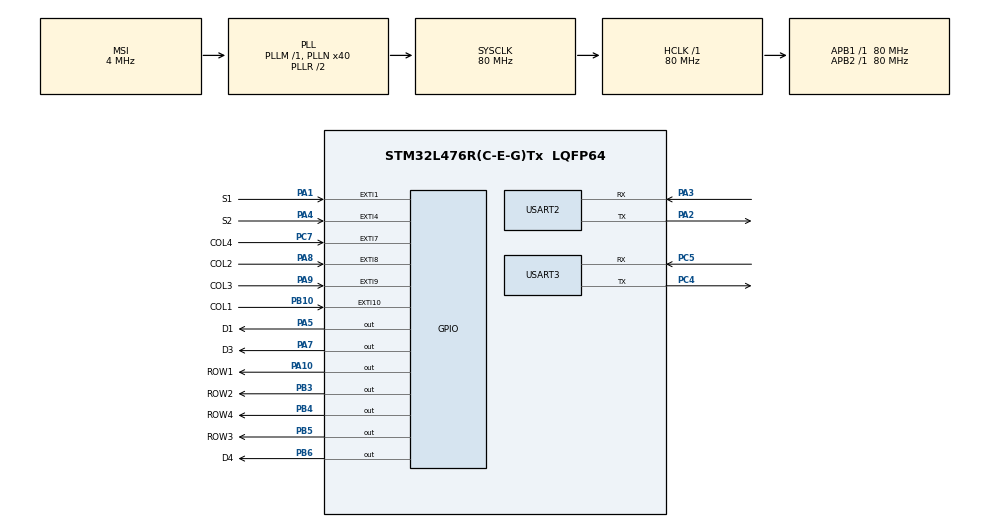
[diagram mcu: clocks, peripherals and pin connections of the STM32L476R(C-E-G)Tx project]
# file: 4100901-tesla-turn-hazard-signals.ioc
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Mcu.Family=STM32L4
Mcu.Name=STM32L476R(C-E-G)Tx
Mcu.Package=LQFP64
NVIC.EXTI15_10_IRQn=true\:0\:0\:false\:false\:true\:true\:true\:true
NVIC.EXTI1_IRQn=true\:0\:0\:false\:false\:true\:true\:true\:true
NVIC.EXTI4_IRQn=true\:0\:0\:false\:false\:true\:true\:true\:true
NVIC.EXTI9_5_IRQn=true\:0\:0\:false\:false\:true\:true\:true\:true
NVIC.PriorityGroup=NVIC_PRIORITYGROUP_4
NVIC.USART2_IRQn=true\:0\:0\:false\:false\:true\:true\:true\:true
NVIC.USART3_IRQn=true\:0\:0\:false\:false\:true\:true\:true\:true
PA1.GPIO_Label=S1
PA1.GPIO_ModeDefaultEXTI=GPIO_MODE_IT_FALLING
PA1.GPIO_PuPd=GPIO_PULLUP
PA1.Signal=GPXTI1
PA10.GPIO_Label=ROW1
PA10.PinState=GPIO_PIN_SET
PA10.Signal=GPIO_Output
PA2.Mode=Asynchronous
PA2.Signal=USART2_TX
PA3.Mode=Asynchronous
PA3.Signal=USART2_RX
PA4.GPIO_Label=S2
PA4.GPIO_ModeDefaultEXTI=GPIO_MODE_IT_FALLING
PA4.GPIO_PuPd=GPIO_PULLUP
PA4.Signal=GPXTI4
PA5.GPIO_Label=D1
PA5.PinState=GPIO_PIN_SET
PA5.Signal=GPIO_Output
PA7.GPIO_Label=D3
PA7.PinState=GPIO_PIN_SET
PA7.Signal=GPIO_Output
PA8.GPIO_Label=COL2
PA8.GPIO_PuPd=GPIO_PULLDOWN
PA8.Signal=GPXTI8
PA9.GPIO_Label=COL3
PA9.GPIO_PuPd=GPIO_PULLDOWN
PA9.Signal=GPXTI9
PB10.GPIO_Label=COL1
PB10.GPIO_PuPd=GPIO_PULLDOWN
PB10.Signal=GPXTI10
PB3\ (JTDO-TRACESWO).GPIO_Label=ROW2
PB3\ (JTDO-TRACESWO).PinState=GPIO_PIN_SET
PB3\ (JTDO-TRACESWO).Signal=GPIO_Output
PB4\ (NJTRST).GPIO_Label=ROW4
PB4\ (NJTRST).PinState=GPIO_PIN_SET
PB4\ (NJTRST).Signal=GPIO_Output
PB5.GPIO_Label=ROW3
PB5.PinState=GPIO_PIN_SET
PB5.Signal=GPIO_Output
PB6.GPIO_Label=D4
PB6.PinState=GPIO_PIN_SET
PB6.Signal=GPIO_Output
PC4.Mode=Asynchronous
PC4.Signal=USART3_TX
PC5.Mode=Asynchronous
PC5.Signal=USART3_RX
PC7.GPIO_Label=COL4
PC7.GPIO_PuPd=GPIO_PULLDOWN
PC7.Signal=GPXTI7
ProjectManager.HeapSize=0x200
ProjectManager.StackSize=0x400
ProjectManager.TargetToolchain=STM32CubeIDE
RCC.AHBFreq_Value=80000000
RCC.APB1Freq_Value=80000000
RCC.APB1TimFreq_Value=80000000
RCC.APB2Freq_Value=80000000
RCC.APB2TimFreq_Value=80000000
RCC.CortexFreq_Value=80000000
RCC.HCLKFreq_Value=80000000
RCC.HSE_VALUE=8000000
RCC.HSI_VALUE=16000000
RCC.LSE_VALUE=32768
RCC.MSI_VALUE=4000000
RCC.PLLN=40
RCC.SYSCLKFreq_VALUE=80000000
RCC.SYSCLKSource=RCC_SYSCLKSOURCE_PLLCLK
RCC.VCOOutputFreq_Value=160000000
USART2.VirtualMode-Asynchronous=VM_ASYNC
USART3.VirtualMode-Asynchronous=VM_ASYNC
board=custom

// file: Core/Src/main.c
/* USER CODE BEGIN Header */
/**
  ******************************************************************************
  * @file           : main.c
  * @brief          : Main program body
  ******************************************************************************
  * @attention
  *
  * Copyright (c) 2024 STMicroelectronics.
  * All rights reserved.
  *
  * This software is licensed under terms that can be found in the LICENSE file
  * in the root directory of this software component.
  * If no LICENSE file comes with this software, it is provided AS-IS.
  *
  ******************************************************************************
  */
/* USER CODE END Header */
#include "main.h"

/* USER CODE BEGIN Includes */
#include "ring_buffer.h"
#include "keypad.h"
/* USER CODE END Includes */

UART_HandleTypeDef huart2;
UART_HandleTypeDef huart3;

/* USER CODE BEGIN PV */
uint32_t left_toggles = 0;
uint32_t left_last_press_tick = 0;

uint8_t data_usart3;
uint8_t data_usart2;

/* control variables for ring buffer in USART3 */
#define CAPACITY_USART3 5
uint8_t mem_usart3[CAPACITY_USART3];
ring_buffer_t rb_usart3;

/* control variables for ring buffer in USART2 */
#define CAPACITY_USART2 10
uint8_t mem_usart2[CAPACITY_USART2];
ring_buffer_t rb_usart2;
/* USER CODE END PV */

void SystemClock_Config(void);
static void MX_GPIO_Init(void);
static void MX_USART2_UART_Init(void);
static void MX_USART3_UART_Init(void);
/* USER CODE BEGIN PFP */
void heartbeat(void);
/* USER CODE END PFP */

/* USER CODE BEGIN 0 */
void HAL_UART_RxCpltCallback(UART_HandleTypeDef *huart)
{
  /* Data received in USART3 */
  if (huart->Instance == USART3) {
	  ring_buffer_write(&rb_usart3, data_usart3);
	  HAL_UART_Receive_IT(&huart3, &data_usart3, 1);
  }
  /* Data received in USART2 */
  if (huart->Instance == USART2) {
	  ring_buffer_write(&rb_usart2, data_usart2); // put the data received in buffer
	  HAL_UART_Receive_IT(&huart2, &data_usart2, 1); // enable interrupt to continue receiving
  }
}

void HAL_GPIO_EXTI_Callback(uint16_t GPIO_Pin)
{
	static uint16_t last_pressed = 0xFFFF;
	static uint32_t last_tick = 0;

	if (last_pressed == GPIO_Pin) {
		if (HAL_GetTick() < (last_tick + 200)) {
			return 0;
		}
	}
	last_pressed = GPIO_Pin;
	last_tick = HAL_GetTick();

	uint8_t key_pressed = keypad_scan(GPIO_Pin);
    HAL_UART_Transmit(&huart2, &key_pressed, 1, 10);

	if (GPIO_Pin == S1_Pin) {
		HAL_UART_Transmit(&huart2, (uint8_t *)"S1\r\n", 4, 10);
		if (HAL_GetTick() < (left_last_press_tick + 300)) { // if last press was in the last 300ms
			left_toggles = 0xFFFFFF; // a long time toggling (infinite)
		} else {
			left_toggles = 6;
		}
		left_last_press_tick = HAL_GetTick();
	} else if (GPIO_Pin == S2_Pin) {
		left_toggles = 0;
	}
}

void heartbeat(void)
{
	static uint32_t heartbeat_tick = 0;
	if (heartbeat_tick < HAL_GetTick()) {
		heartbeat_tick = HAL_GetTick() + 500;
		HAL_GPIO_TogglePin(D1_GPIO_Port, D1_Pin);
	}
}

void turn_signal_left(void)
{
	static uint32_t turn_toggle_tick = 0;
	if (turn_toggle_tick < HAL_GetTick()) {
		if (left_toggles > 0) {
			turn_toggle_tick = HAL_GetTick() + 500;
			HAL_GPIO_TogglePin(D3_GPIO_Port, D3_Pin);
			left_toggles--;
		} else {
			HAL_GPIO_WritePin(D3_GPIO_Port, D3_Pin, 1);
		}

	}
}
/* USER CODE END 0 */

int main(void)
{

  /* MCU Configuration--------------------------------------------------------*/

  /* Reset of all peripherals, Initializes the Flash interface and the Systick. */
  HAL_Init();

  /* Configure the system clock */
  SystemClock_Config();

  /* Initialize all configured peripherals */
  MX_GPIO_Init();
  MX_USART2_UART_Init();
  MX_USART3_UART_Init();
  /* USER CODE BEGIN 2 */
  /* Initialize ring buffer (control, memory, and capacity) */
  ring_buffer_init(&rb_usart3, mem_usart3, CAPACITY_USART3);
  ring_buffer_init(&rb_usart2, mem_usart2, CAPACITY_USART2);
  /* USER CODE END 2 */

  /* Infinite loop */
  /* USER CODE BEGIN WHILE */
  /* Enable USART Rx interrupt to start receiving */
  HAL_UART_Receive_IT(&huart3, &data_usart3, 1);
  HAL_UART_Receive_IT(&huart2, &data_usart2, 1);
  while (1)
  {
	  uint8_t byte = 0;
	  if (ring_buffer_is_full(&rb_usart2) != 0) {
		  int8_t id_incorrect = 0;
		  char my_id[] = "1053821948";
		  for (uint8_t idx = 0; idx < sizeof(my_id); idx++) {
			  if (ring_buffer_read(&rb_usart2, &byte) != 0) { // 0x20
				  if (byte != my_id[idx]) {
					  id_incorrect = 1;
				  }
			  }
		  }
		  if (id_incorrect == 0) {
			  HAL_UART_Transmit(&huart2, "Sam C\r\n", 7, 10);
		  } else {
			  HAL_UART_Transmit(&huart2, "Error\r\n", 7, 10);
		  }
	  }
	  if (ring_buffer_is_empty(&rb_usart3) == 0) {
		  uint8_t data;
		  ring_buffer_read(&rb_usart3, &data);
		  HAL_UART_Transmit(&huart2, &data, 1, 10);
	  }
	  heartbeat();
	  turn_signal_left();
    /* USER CODE END WHILE */

  }
}

void SystemClock_Config(void)
{
  RCC_OscInitTypeDef RCC_OscInitStruct = {0};
  RCC_ClkInitTypeDef RCC_ClkInitStruct = {0};

  /** Configure the main internal regulator output voltage
  */
  if (HAL_PWREx_ControlVoltageScaling(PWR_REGULATOR_VOLTAGE_SCALE1) != HAL_OK)
  {
    Error_Handler();
  }

  /** Initializes the RCC Oscillators according to the specified parameters
  * in the RCC_OscInitTypeDef structure.
  */
  RCC_OscInitStruct.OscillatorType = RCC_OSCILLATORTYPE_MSI;
  RCC_OscInitStruct.MSIState = RCC_MSI_ON;
  RCC_OscInitStruct.MSICalibrationValue = 0;
  RCC_OscInitStruct.MSIClockRange = RCC_MSIRANGE_6;
  RCC_OscInitStruct.PLL.PLLState = RCC_PLL_ON;
  RCC_OscInitStruct.PLL.PLLSource = RCC_PLLSOURCE_MSI;
  RCC_OscInitStruct.PLL.PLLM = 1;
  RCC_OscInitStruct.PLL.PLLN = 40;
  RCC_OscInitStruct.PLL.PLLP = RCC_PLLP_DIV7;
  RCC_OscInitStruct.PLL.PLLQ = RCC_PLLQ_DIV2;
  RCC_OscInitStruct.PLL.PLLR = RCC_PLLR_DIV2;
  if (HAL_RCC_OscConfig(&RCC_OscInitStruct) != HAL_OK)
  {
    Error_Handler();
  }

  /** Initializes the CPU, AHB and APB buses clocks
  */
  RCC_ClkInitStruct.ClockType = RCC_CLOCKTYPE_HCLK|RCC_CLOCKTYPE_SYSCLK
                              |RCC_CLOCKTYPE_PCLK1|RCC_CLOCKTYPE_PCLK2;
  RCC_ClkInitStruct.SYSCLKSource = RCC_SYSCLKSOURCE_PLLCLK;
  RCC_ClkInitStruct.AHBCLKDivider = RCC_SYSCLK_DIV1;
  RCC_ClkInitStruct.APB1CLKDivider = RCC_HCLK_DIV1;
  RCC_ClkInitStruct.APB2CLKDivider = RCC_HCLK_DIV1;

  if (HAL_RCC_ClockConfig(&RCC_ClkInitStruct, FLASH_LATENCY_4) != HAL_OK)
  {
    Error_Handler();
  }
}

static void MX_USART2_UART_Init(void)
{

  huart2.Instance = USART2;
  huart2.Init.BaudRate = 115200;
  huart2.Init.WordLength = UART_WORDLENGTH_8B;
  huart2.Init.StopBits = UART_STOPBITS_1;
  huart2.Init.Parity = UART_PARITY_NONE;
  huart2.Init.Mode = UART_MODE_TX_RX;
  huart2.Init.HwFlowCtl = UART_HWCONTROL_NONE;
  huart2.Init.OverSampling = UART_OVERSAMPLING_16;
  huart2.Init.OneBitSampling = UART_ONE_BIT_SAMPLE_DISABLE;
  huart2.AdvancedInit.AdvFeatureInit = UART_ADVFEATURE_NO_INIT;
  if (HAL_UART_Init(&huart2) != HAL_OK)
  {
    Error_Handler();
  }

}

static void MX_USART3_UART_Init(void)
{

  huart3.Instance = USART3;
  huart3.Init.BaudRate = 115200;
  huart3.Init.WordLength = UART_WORDLENGTH_8B;
  huart3.Init.StopBits = UART_STOPBITS_1;
  huart3.Init.Parity = UART_PARITY_NONE;
  huart3.Init.Mode = UART_MODE_TX_RX;
  huart3.Init.HwFlowCtl = UART_HWCONTROL_NONE;
  huart3.Init.OverSampling = UART_OVERSAMPLING_16;
  huart3.Init.OneBitSampling = UART_ONE_BIT_SAMPLE_DISABLE;
  huart3.AdvancedInit.AdvFeatureInit = UART_ADVFEATURE_NO_INIT;
  if (HAL_UART_Init(&huart3) != HAL_OK)
  {
    Error_Handler();
  }

}

static void MX_GPIO_Init(void)
{
  GPIO_InitTypeDef GPIO_InitStruct = {0};

  /* GPIO Ports Clock Enable */
  __HAL_RCC_GPIOA_CLK_ENABLE();
  __HAL_RCC_GPIOC_CLK_ENABLE();
  __HAL_RCC_GPIOB_CLK_ENABLE();

  /*Configure GPIO pin Output Level */
  HAL_GPIO_WritePin(GPIOA, D1_Pin|D3_Pin|ROW1_Pin, GPIO_PIN_SET);

  /*Configure GPIO pin Output Level */
  HAL_GPIO_WritePin(GPIOB, ROW2_Pin|ROW4_Pin|ROW3_Pin|D4_Pin, GPIO_PIN_SET);

  /*Configure GPIO pins : S1_Pin S2_Pin */
  GPIO_InitStruct.Pin = S1_Pin|S2_Pin;
  GPIO_InitStruct.Mode = GPIO_MODE_IT_FALLING;
  GPIO_InitStruct.Pull = GPIO_PULLUP;
  HAL_GPIO_Init(GPIOA, &GPIO_InitStruct);

  /*Configure GPIO pins : D1_Pin D3_Pin ROW1_Pin */
  GPIO_InitStruct.Pin = D1_Pin|D3_Pin|ROW1_Pin;
  GPIO_InitStruct.Mode = GPIO_MODE_OUTPUT_PP;
  GPIO_InitStruct.Pull = GPIO_NOPULL;
  GPIO_InitStruct.Speed = GPIO_SPEED_FREQ_LOW;
  HAL_GPIO_Init(GPIOA, &GPIO_InitStruct);

  /*Configure GPIO pin : COLUMN1_Pin */
  GPIO_InitStruct.Pin = COLUMN1_Pin;
  GPIO_InitStruct.Mode = GPIO_MODE_IT_RISING;
  GPIO_InitStruct.Pull = GPIO_PULLDOWN;
  HAL_GPIO_Init(COLUMN1_GPIO_Port, &GPIO_InitStruct);

  /*Configure GPIO pin : COLUMN4_Pin */
  GPIO_InitStruct.Pin = COLUMN4_Pin;
  GPIO_InitStruct.Mode = GPIO_MODE_IT_RISING;
  GPIO_InitStruct.Pull = GPIO_PULLDOWN;
  HAL_GPIO_Init(COLUMN4_GPIO_Port, &GPIO_InitStruct);

  /*Configure GPIO pins : COLUMN2_Pin COLUMN3_Pin */
  GPIO_InitStruct.Pin = COLUMN2_Pin|COLUMN3_Pin;
  GPIO_InitStruct.Mode = GPIO_MODE_IT_RISING;
  GPIO_InitStruct.Pull = GPIO_PULLDOWN;
  HAL_GPIO_Init(GPIOA, &GPIO_InitStruct);

  /*Configure GPIO pins : ROW2_Pin ROW4_Pin ROW3_Pin D4_Pin */
  GPIO_InitStruct.Pin = ROW2_Pin|ROW4_Pin|ROW3_Pin|D4_Pin;
  GPIO_InitStruct.Mode = GPIO_MODE_OUTPUT_PP;
  GPIO_InitStruct.Pull = GPIO_NOPULL;
  GPIO_InitStruct.Speed = GPIO_SPEED_FREQ_LOW;
  HAL_GPIO_Init(GPIOB, &GPIO_InitStruct);

  /* EXTI interrupt init*/
  HAL_NVIC_SetPriority(EXTI1_IRQn, 0, 0);
  HAL_NVIC_EnableIRQ(EXTI1_IRQn);

  HAL_NVIC_SetPriority(EXTI4_IRQn, 0, 0);
  HAL_NVIC_EnableIRQ(EXTI4_IRQn);

  HAL_NVIC_SetPriority(EXTI9_5_IRQn, 0, 0);
  HAL_NVIC_EnableIRQ(EXTI9_5_IRQn);

  HAL_NVIC_SetPriority(EXTI15_10_IRQn, 0, 0);
  HAL_NVIC_EnableIRQ(EXTI15_10_IRQn);

}

void Error_Handler(void)
{
  __disable_irq();
  while (1)
  {
  }
}
